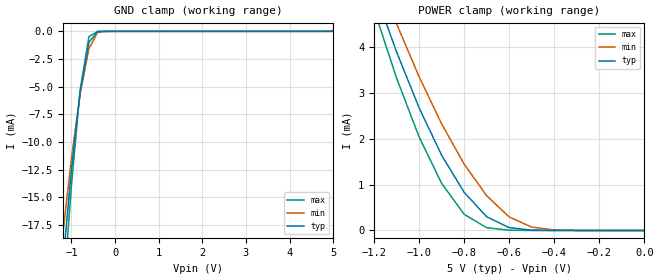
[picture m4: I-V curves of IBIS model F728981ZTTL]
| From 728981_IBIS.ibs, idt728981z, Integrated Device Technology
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|   Model F728981ZTTL
[Model]   F728981ZTTL
Model_type   Input
Vinl =  0.000V
Vinh =  3.000V
Vmeas =  1.500V
C_comp   3.00pF   NA   NA
[Temperature Range]   25.00   85.00   -40.00
[Voltage Range]   5.00V   4.50V   5.50V
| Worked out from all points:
|   GND clamp passes 1 mA (typ) near -0.60 V on its own axis
|   POWER clamp passes 1 mA (typ) near -0.82 V on its own axis
[GND_clamp]
| voltage   I(typ)   I(min)   I(max)
-5V       -230mA     -201mA     -262mA
-1.2V     -21.09mA   -18.4mA    -24.48mA
-1V       -12.49mA   -11.43mA   -13.86mA
-800mV    -5.437mA   -5.618mA   -5.219mA
-600mV    -980uA     -1.556mA   -466uA
-400mV    -16.84uA   -86.28uA   -1.717uA
-200mV    -25.43nA   -650nA     -2.668nA
4.8V      48.17nA    1.3uA      48.1nA
5V        50.2nA     73.15uA    50.12nA
[POWER_clamp]
| voltage   I(typ)   I(min)   I(max)
-5V       85.15mA    78.53mA    92.86mA
-1.2V     5.278mA    5.785mA    4.832mA
-1.1V     3.903mA    4.518mA    3.33mA
-1V       2.681mA    3.36mA     2.046mA
-900mV    1.645mA    2.329mA    1.03mA
-800mV    834uA      1.451mA    354uA
-700mV    300uA      759uA      61.46uA
-600mV    62.49uA    295uA      5.753uA
-500mV    7.622uA    73.15uA    365nA
-400mV    634nA      11.44uA    66.37nA
0V        50.2nA     48.82nA    55.18nA
